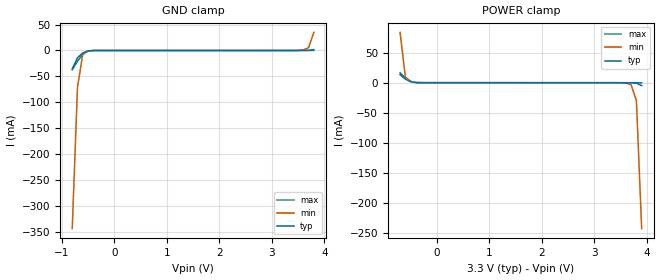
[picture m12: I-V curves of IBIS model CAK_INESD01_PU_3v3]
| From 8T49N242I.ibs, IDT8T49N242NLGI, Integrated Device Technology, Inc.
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[Model] CAK_INESD01_PU_3v3
Model_type   Input
Polarity   Non-Inverting
Vinl = 0.8V
Vinh = 2.0V
|   typ   min   max
C_comp   2pF   1.5pF   2.5pF
|   typ   min   max
[Voltage range]   3.3V   3.135V   3.465V
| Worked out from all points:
|   GND clamp passes 1 mA (typ) near -0.50 V on its own axis
|   POWER clamp passes 1 mA (typ) near -0.45 V on its own axis
[GND_clamp]
|Voltage   I (typ)   I (min)   I (max)
|Note, modeling breaks down at 250mA and above.  This is well beyond the functional   |
|operating range of the device.  Should this scenario occur, catastrophic failure and   |
|possible damage to the device and/or board is of higher concern than the I-V curve   |
|behavior.  The IBIS checker will flag currents in excess of 10A with warnings.  Lines   |
|with currents in excess of 0.35 A have been commented out.  The points still remain|
|available to the user if the user desires to use them.   |
|-3.30000e+00   -9.41633e+00   -7.46544e+00   -1.16029e+01
|-3.20000e+00   -9.03423e+00   -7.17870e+00   -1.11157e+01
|-3.10000e+00   -8.65215e+00   -6.89204e+00   -1.06284e+01
|-3.00000e+00   -8.27008e+00   -6.60546e+00   -1.01412e+01
|-2.90000e+00   -7.88804e+00   -6.31897e+00   -9.65394e+00
|-2.80000e+00   -7.50603e+00   -6.03258e+00   -9.16668e+00
|-2.70000e+00   -7.12406e+00   -5.74630e+00   -8.67940e+00
|-2.60000e+00   -6.74214e+00   -5.46013e+00   -8.19212e+00
|-2.50000e+00   -6.36027e+00   -5.17408e+00   -7.70484e+00
|-2.40000e+00   -5.97847e+00   -4.88817e+00   -7.21758e+00
|-2.30000e+00   -5.59676e+00   -4.60240e+00   -6.73034e+00
|-2.20000e+00   -5.21514e+00   -4.31678e+00   -6.24313e+00
|-2.10000e+00   -4.83364e+00   -4.03134e+00   -5.75598e+00
|-2.00000e+00   -4.45227e+00   -3.74608e+00   -5.26891e+00
|-1.90000e+00   -4.07106e+00   -3.46102e+00   -4.78194e+00
|-1.80000e+00   -3.69004e+00   -3.17617e+00   -4.29510e+00
|-1.70000e+00   -3.30923e+00   -2.89154e+00   -3.80842e+00
|-1.60000e+00   -2.92868e+00   -2.60717e+00   -3.32192e+00
|-1.50000e+00   -2.54841e+00   -2.32305e+00   -2.83563e+00
|-1.40000e+00   -2.16847e+00   -2.03921e+00   -2.34960e+00
|-1.30000e+00   -1.78891e+00   -1.75565e+00   -1.86389e+00
|-1.20000e+00   -1.40978e+00   -1.47241e+00   -1.37858e+00
|-1.10000e+00   -1.03112e+00   -1.18950e+00   -8.93754e-01
|-1.00000e+00   -6.52996e-01   -9.06976e-01   -4.09495e-01
|-9.00000e-01   -2.75471e-01   -6.24988e-01   -6.11749e-02
-800mV    -35.49mA   -343.8mA   -37.17mA
-700mV    -14.12mA   -71.44mA   -20.86mA
-600mV    -4.894mA   -7.5mA     -7.57mA
-500mV    -845.3uA   -1.039mA   -1.201mA
-400mV    -124.1uA   -159.5uA   -141.9uA
3.5V      4.074uA    132.9uA    805.5nA
3.6V      12.51uA    1.151mA    3.107uA
3.7V      188uA      5.395mA    5.575uA
3.8V      1.749mA    34.86mA    23.47uA
| 3.90000e+00   6.00763e-03   3.75551e-01   5.18212e-04
| 4.00000e+00   1.32587e-02   9.48201e-01   3.67695e-03
| 4.10000e+00   3.25479e-02   1.52028e+00   1.03297e-02
| 4.20000e+00   4.12425e-01   2.09265e+00   2.01826e-02
| 4.30000e+00   1.17634e+00   2.66539e+00   2.99759e-02
| 4.40000e+00   1.94072e+00   3.23850e+00   1.00627e-01
| 4.50000e+00   2.70560e+00   3.81198e+00   9.84992e-01
| 4.60000e+00   3.47098e+00   4.38583e+00   1.96269e+00
| 4.70000e+00   4.23685e+00   4.96005e+00   2.94102e+00
| 4.80000e+00   5.00320e+00   5.53463e+00   3.91995e+00
| 4.90000e+00   5.77000e+00   6.10959e+00   4.89948e+00
| 5.00000e+00   6.53726e+00   6.68491e+00   5.87956e+00
| 5.10000e+00   7.30496e+00   7.26060e+00   6.86018e+00
| 5.20000e+00   8.07309e+00   7.83665e+00   7.84132e+00
| 5.30000e+00   8.84165e+00   8.41309e+00   8.82296e+00
| 5.40000e+00   9.61063e+00   8.98990e+00   9.80507e+00
| 5.50000e+00   1.03800e+01   9.56710e+00   1.07877e+01
| 5.60000e+00   1.11498e+01   1.01447e+01   1.17707e+01
| 5.70000e+00   1.19201e+01   1.07227e+01   1.27541e+01
| 5.80000e+00   1.26907e+01   1.13011e+01   1.37380e+01
| 5.90000e+00   1.34618e+01   1.18800e+01   1.47224e+01
| 6.00000e+00   1.42332e+01   1.24593e+01   1.57071e+01
| 6.10000e+00   1.50052e+01   1.30391e+01   1.66923e+01
| 6.20000e+00   1.57776e+01   1.36194e+01   1.76779e+01
| 6.30000e+00   1.65504e+01   1.42001e+01   1.86639e+01
| 6.40000e+00   1.73237e+01   1.47815e+01   1.96503e+01
| 6.50000e+00   1.80975e+01   1.53633e+01   2.06372e+01
| 6.60000e+00   1.88719e+01   1.59458e+01   2.16246e+01
[Power_clamp]
|Voltage   I (typ)   I (min)   I (max)
|Note, modeling breaks down at 250mA and above.  This is well beyond the functional   |
|operating range of the device.  Should this scenario occur, catastrophic failure and   |
|possible damage to the device and/or board is of higher concern than the I-V curve   |
|behavior.  The IBIS checker will flag currents in excess of 10A with warnings.  Lines   |
|with currents in excess of 0.35 A have been commented out.  The points still remain|
|available to the user if the user desires to use them.   |
|-3.30000e+00   1.88719e+01   1.49909e+01   2.32548e+01
|-3.20000e+00   1.80975e+01   1.44093e+01   2.22666e+01
|-3.10000e+00   1.73237e+01   1.38284e+01   2.12789e+01
|-3.00000e+00   1.65504e+01   1.32479e+01   2.02918e+01
|-2.90000e+00   1.57776e+01   1.26680e+01   1.93050e+01
|-2.80000e+00   1.50052e+01   1.20885e+01   1.83187e+01
|-2.70000e+00   1.42332e+01   1.15095e+01   1.73328e+01
|-2.60000e+00   1.34618e+01   1.09309e+01   1.63474e+01
|-2.50000e+00   1.26907e+01   1.03527e+01   1.53624e+01
|-2.40000e+00   1.19201e+01   9.77499e+00   1.43778e+01
|-2.30000e+00   1.11498e+01   9.19765e+00   1.33936e+01
|-2.20000e+00   1.03800e+01   8.62070e+00   1.24099e+01
|-2.10000e+00   9.61063e+00   8.04413e+00   1.14266e+01
|-2.00000e+00   8.84165e+00   7.46793e+00   1.04437e+01
|-1.90000e+00   8.07309e+00   6.89211e+00   9.46128e+00
|-1.80000e+00   7.30496e+00   6.31666e+00   8.47933e+00
|-1.70000e+00   6.53726e+00   5.74158e+00   7.49787e+00
|-1.60000e+00   5.77000e+00   5.16686e+00   6.51690e+00
|-1.50000e+00   5.00320e+00   4.59250e+00   5.53647e+00
|-1.40000e+00   4.23685e+00   4.01852e+00   4.55658e+00
|-1.30000e+00   3.47098e+00   3.44491e+00   3.57726e+00
|-1.20000e+00   2.70560e+00   2.87167e+00   2.59853e+00
|-1.10000e+00   1.94072e+00   2.29880e+00   1.62043e+00
|-1.00000e+00   1.17634e+00   1.72630e+00   6.42946e-01
|-9.00000e-01   4.12425e-01   1.15413e+00   4.60266e-02
|-8.00000e-01   3.25479e-02   5.81954e-01   2.67526e-02
-700mV    13.26mA    83.51mA    16.45mA
-600mV    6.008mA    9.635mA    7.61mA
-500mV    1.749mA    2.079mA    2.168mA
-300mV    12.51uA    26.28uA    10.83uA
3.5V      -69.76uA   -100.7uA   -80.55uA
3.6V      -73.38uA   -506uA     -82.85uA
3.7V      -124.1uA   -3.671mA   -85.19uA
3.8V      -845.3uA   -29.99mA   -91.47uA
3.9V      -4.894mA   -242.4mA   -262.6uA
